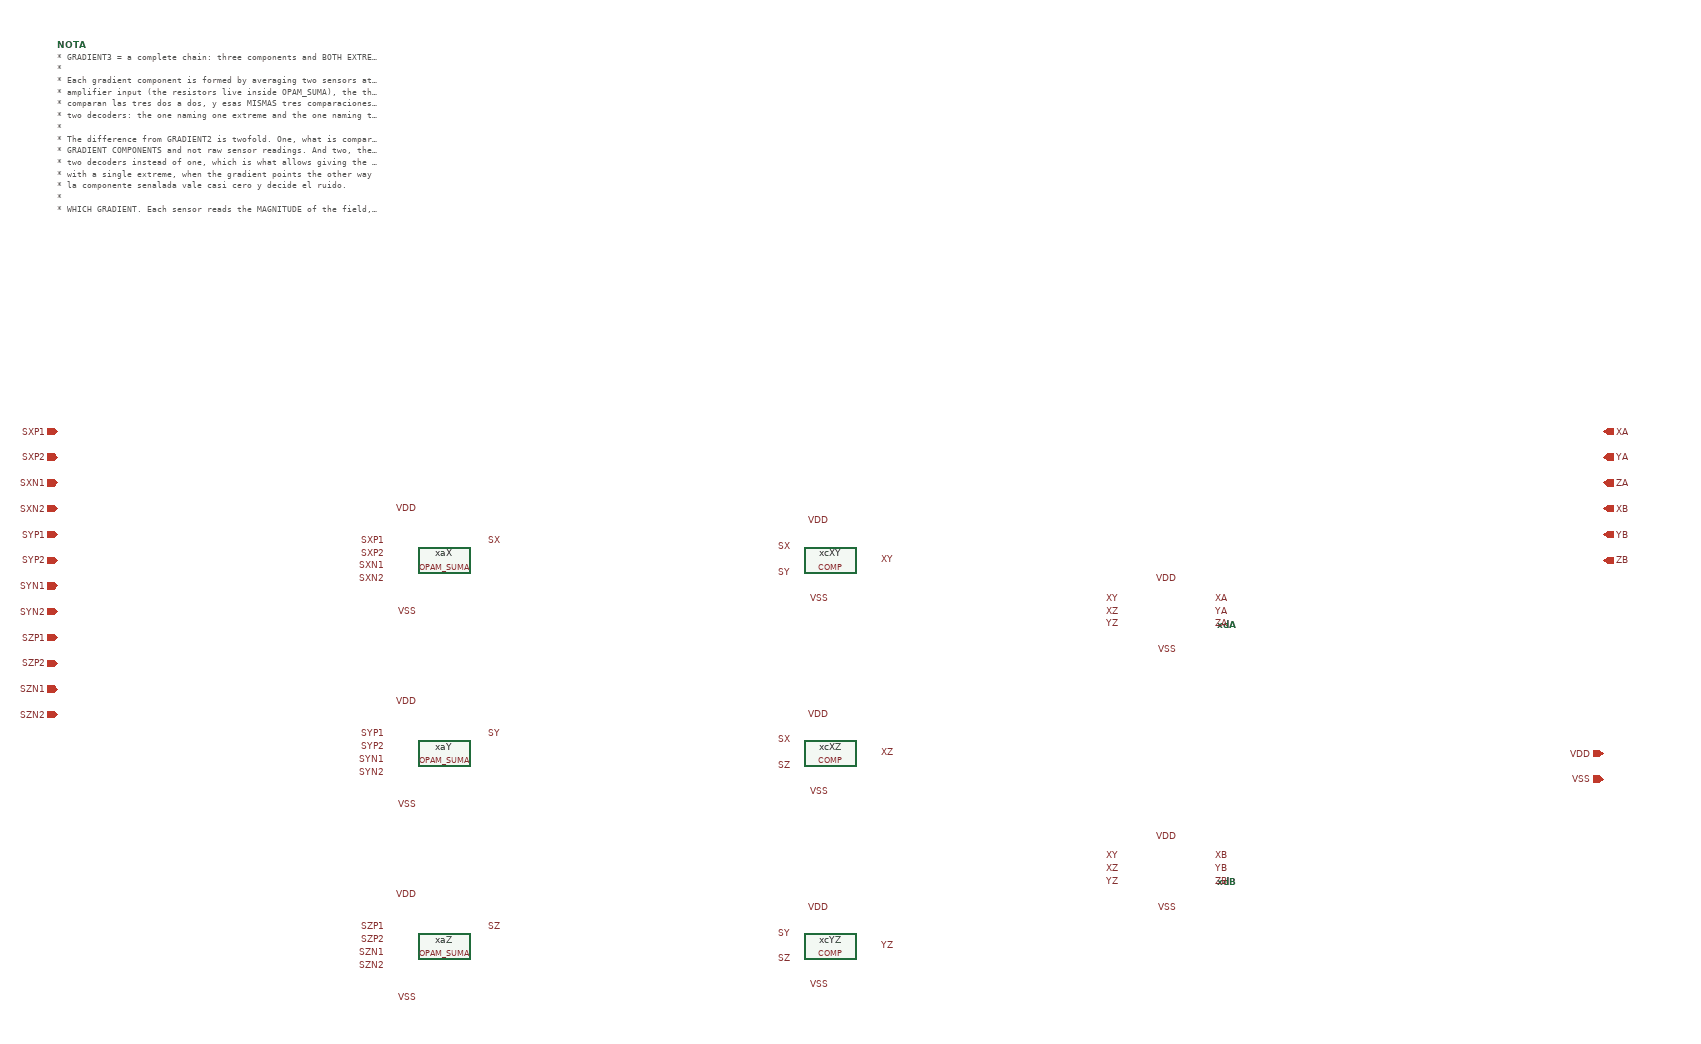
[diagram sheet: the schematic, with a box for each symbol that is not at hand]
v {xschem version=3.4.8RC file_version=1.3}
G {}
K {}
V {}
S {}
F {}
E {}
C {a_zonetic2026/XSCHEM_v2/OPAM_SUMA.sym} -600 -400 0 0 {name=xaX}
C {devices/lab_pin.sym} -690.0 -430.0 0 0 {name=l1 sig_type=std_logic lab=SXP1}
C {devices/lab_pin.sym} -690.0 -410.0 0 0 {name=l2 sig_type=std_logic lab=SXP2}
C {devices/lab_pin.sym} -690.0 -390.0 0 0 {name=l3 sig_type=std_logic lab=SXN1}
C {devices/lab_pin.sym} -690.0 -370.0 0 0 {name=l4 sig_type=std_logic lab=SXN2}
C {devices/lab_pin.sym} -510.0 -430.0 0 0 {name=l5 sig_type=std_logic lab=SX}
C {devices/lab_pin.sym} -640.0 -480.0 0 0 {name=l6 sig_type=std_logic lab=VDD}
C {devices/lab_pin.sym} -640.0 -320.0 0 0 {name=l7 sig_type=std_logic lab=VSS}
C {a_zonetic2026/XSCHEM_v2/OPAM_SUMA.sym} -600 -100 0 0 {name=xaY}
C {devices/lab_pin.sym} -690.0 -130.0 0 0 {name=l8 sig_type=std_logic lab=SYP1}
C {devices/lab_pin.sym} -690.0 -110.0 0 0 {name=l9 sig_type=std_logic lab=SYP2}
C {devices/lab_pin.sym} -690.0 -90.0 0 0 {name=l10 sig_type=std_logic lab=SYN1}
C {devices/lab_pin.sym} -690.0 -70.0 0 0 {name=l11 sig_type=std_logic lab=SYN2}
C {devices/lab_pin.sym} -510.0 -130.0 0 0 {name=l12 sig_type=std_logic lab=SY}
C {devices/lab_pin.sym} -640.0 -180.0 0 0 {name=l13 sig_type=std_logic lab=VDD}
C {devices/lab_pin.sym} -640.0 -20.0 0 0 {name=l14 sig_type=std_logic lab=VSS}
C {a_zonetic2026/XSCHEM_v2/OPAM_SUMA.sym} -600 200 0 0 {name=xaZ}
C {devices/lab_pin.sym} -690.0 170.0 0 0 {name=l15 sig_type=std_logic lab=SZP1}
C {devices/lab_pin.sym} -690.0 190.0 0 0 {name=l16 sig_type=std_logic lab=SZP2}
C {devices/lab_pin.sym} -690.0 210.0 0 0 {name=l17 sig_type=std_logic lab=SZN1}
C {devices/lab_pin.sym} -690.0 230.0 0 0 {name=l18 sig_type=std_logic lab=SZN2}
C {devices/lab_pin.sym} -510.0 170.0 0 0 {name=l19 sig_type=std_logic lab=SZ}
C {devices/lab_pin.sym} -640.0 120.0 0 0 {name=l20 sig_type=std_logic lab=VDD}
C {devices/lab_pin.sym} -640.0 280.0 0 0 {name=l21 sig_type=std_logic lab=VSS}
C {a_zonetic2026/XSCHEM/OPAM/COMP.sym} 0 -400 0 0 {name=xcXY}
C {devices/lab_pin.sym} 0.0 -460.0 0 0 {name=l22 sig_type=std_logic lab=VDD}
C {devices/lab_pin.sym} -60.0 -420.0 0 0 {name=l23 sig_type=std_logic lab=SX}
C {devices/lab_pin.sym} 100.0 -400.0 0 0 {name=l24 sig_type=std_logic lab=XY}
C {devices/lab_pin.sym} -60.0 -380.0 0 0 {name=l25 sig_type=std_logic lab=SY}
C {devices/lab_pin.sym} 0.0 -340.0 0 0 {name=l26 sig_type=std_logic lab=VSS}
C {a_zonetic2026/XSCHEM/OPAM/COMP.sym} 0 -100 0 0 {name=xcXZ}
C {devices/lab_pin.sym} 0.0 -160.0 0 0 {name=l27 sig_type=std_logic lab=VDD}
C {devices/lab_pin.sym} -60.0 -120.0 0 0 {name=l28 sig_type=std_logic lab=SX}
C {devices/lab_pin.sym} 100.0 -100.0 0 0 {name=l29 sig_type=std_logic lab=XZ}
C {devices/lab_pin.sym} -60.0 -80.0 0 0 {name=l30 sig_type=std_logic lab=SZ}
C {devices/lab_pin.sym} 0.0 -40.0 0 0 {name=l31 sig_type=std_logic lab=VSS}
C {a_zonetic2026/XSCHEM/OPAM/COMP.sym} 0 200 0 0 {name=xcYZ}
C {devices/lab_pin.sym} 0.0 140.0 0 0 {name=l32 sig_type=std_logic lab=VDD}
C {devices/lab_pin.sym} -60.0 180.0 0 0 {name=l33 sig_type=std_logic lab=SY}
C {devices/lab_pin.sym} 100.0 200.0 0 0 {name=l34 sig_type=std_logic lab=YZ}
C {devices/lab_pin.sym} -60.0 220.0 0 0 {name=l35 sig_type=std_logic lab=SZ}
C {devices/lab_pin.sym} 0.0 260.0 0 0 {name=l36 sig_type=std_logic lab=VSS}
C {a_zonetic2026/XSCHEM/DECODER/DECODER.sym} 600 -300 0 0 {name=xdA}
C {devices/lab_pin.sym} 540.0 -370.0 0 0 {name=l37 sig_type=std_logic lab=VDD}
C {devices/lab_pin.sym} 450.0 -340.0 0 0 {name=l38 sig_type=std_logic lab=XY}
C {devices/lab_pin.sym} 450.0 -320.0 0 0 {name=l39 sig_type=std_logic lab=XZ}
C {devices/lab_pin.sym} 620.0 -340.0 0 0 {name=l40 sig_type=std_logic lab=XA}
C {devices/lab_pin.sym} 620.0 -320.0 0 0 {name=l41 sig_type=std_logic lab=YA}
C {devices/lab_pin.sym} 450.0 -300.0 0 0 {name=l42 sig_type=std_logic lab=YZ}
C {devices/lab_pin.sym} 620.0 -300.0 0 0 {name=l43 sig_type=std_logic lab=ZA}
C {devices/lab_pin.sym} 540.0 -260.0 0 0 {name=l44 sig_type=std_logic lab=VSS}
C {a_zonetic2026/XSCHEM_v2/DECODER_MAX.sym} 600 100 0 0 {name=xdB}
C {devices/lab_pin.sym} 540.0 30.0 0 0 {name=l45 sig_type=std_logic lab=VDD}
C {devices/lab_pin.sym} 450.0 60.0 0 0 {name=l46 sig_type=std_logic lab=XY}
C {devices/lab_pin.sym} 450.0 80.0 0 0 {name=l47 sig_type=std_logic lab=XZ}
C {devices/lab_pin.sym} 620.0 60.0 0 0 {name=l48 sig_type=std_logic lab=XB}
C {devices/lab_pin.sym} 620.0 80.0 0 0 {name=l49 sig_type=std_logic lab=YB}
C {devices/lab_pin.sym} 450.0 100.0 0 0 {name=l50 sig_type=std_logic lab=YZ}
C {devices/lab_pin.sym} 620.0 100.0 0 0 {name=l51 sig_type=std_logic lab=ZB}
C {devices/lab_pin.sym} 540.0 140.0 0 0 {name=l52 sig_type=std_logic lab=VSS}
C {ipin.sym} -1200 -600 0 0 {name=q53 lab=SXP1}
C {ipin.sym} -1200 -560 0 0 {name=q54 lab=SXP2}
C {ipin.sym} -1200 -520 0 0 {name=q55 lab=SXN1}
C {ipin.sym} -1200 -480 0 0 {name=q56 lab=SXN2}
C {ipin.sym} -1200 -440 0 0 {name=q57 lab=SYP1}
C {ipin.sym} -1200 -400 0 0 {name=q58 lab=SYP2}
C {ipin.sym} -1200 -360 0 0 {name=q59 lab=SYN1}
C {ipin.sym} -1200 -320 0 0 {name=q60 lab=SYN2}
C {ipin.sym} -1200 -280 0 0 {name=q61 lab=SZP1}
C {ipin.sym} -1200 -240 0 0 {name=q62 lab=SZP2}
C {ipin.sym} -1200 -200 0 0 {name=q63 lab=SZN1}
C {ipin.sym} -1200 -160 0 0 {name=q64 lab=SZN2}
C {opin.sym} 1200 -600 0 0 {name=q65 lab=XA}
C {opin.sym} 1200 -560 0 0 {name=q66 lab=YA}
C {opin.sym} 1200 -520 0 0 {name=q67 lab=ZA}
C {opin.sym} 1200 -480 0 0 {name=q68 lab=XB}
C {opin.sym} 1200 -440 0 0 {name=q69 lab=YB}
C {opin.sym} 1200 -400 0 0 {name=q70 lab=ZB}
C {iopin.sym} 1200 -100 0 0 {name=q71 lab=VDD}
C {iopin.sym} 1200 -60 0 0 {name=q72 lab=VSS}
C {devices/code_shown.sym} -1200 -1200 0 0 {name=NOTA only_toplevel=false
value="* GRADIENT3 = a complete chain: three components and BOTH EXTREMES.
*
* Each gradient component is formed by averaging two sensors at the
* amplifier input (the resistors live inside OPAM_SUMA), the three are
* comparan las tres dos a dos, y esas MISMAS tres comparaciones alimentan
* two decoders: the one naming one extreme and the one naming the other.
*
* The difference from GRADIENT2 is twofold. One, what is compared are
* GRADIENT COMPONENTS and not raw sensor readings. And two, there are
* two decoders instead of one, which is what allows giving the SENSE:
* with a single extreme, when the gradient points the other way
* la componente senalada vale casi cero y decide el ruido.
*
* WHICH GRADIENT. Each sensor reads the MAGNITUDE of the field, |B|, at
* its position: a scalar. The four sample that scalar field and what is
* reconstructed is grad|B|, which points where the magnitude GROWS, that
* hacia la fuente.
*
* A and B are the two extremes. Which is the minimum and which the
* maximum depends on the analogue chain sign, so it is fixed by MEASURING.
* Medido: el lado B es el maximo, o sea el que apunta hacia la fuente."}
